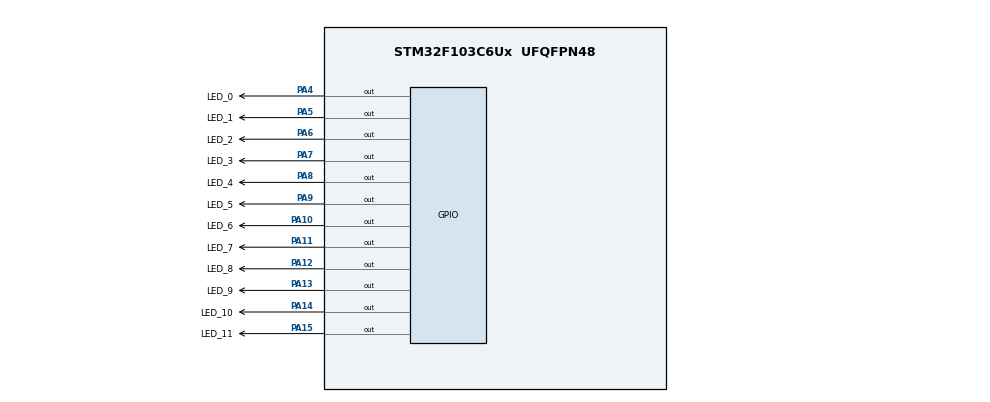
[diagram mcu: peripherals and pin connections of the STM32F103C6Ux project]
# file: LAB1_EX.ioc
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Mcu.Family=STM32F1
Mcu.Name=STM32F103C6Ux
Mcu.Package=UFQFPN48
NVIC.PriorityGroup=NVIC_PRIORITYGROUP_4
PA10.GPIO_Label=LED_6
PA10.Signal=GPIO_Output
PA11.GPIO_Label=LED_7
PA11.Signal=GPIO_Output
PA12.GPIO_Label=LED_8
PA12.Signal=GPIO_Output
PA13.GPIO_Label=LED_9
PA13.Signal=GPIO_Output
PA14.GPIO_Label=LED_10
PA14.Signal=GPIO_Output
PA15.GPIO_Label=LED_11
PA15.Signal=GPIO_Output
PA4.GPIO_Label=LED_0
PA4.Signal=GPIO_Output
PA5.GPIO_Label=LED_1
PA5.Signal=GPIO_Output
PA6.GPIO_Label=LED_2
PA6.Signal=GPIO_Output
PA7.GPIO_Label=LED_3
PA7.Signal=GPIO_Output
PA8.GPIO_Label=LED_4
PA8.Signal=GPIO_Output
PA9.GPIO_Label=LED_5
PA9.Signal=GPIO_Output
ProjectManager.HeapSize=0x200
ProjectManager.StackSize=0x400
ProjectManager.TargetToolchain=STM32CubeIDE
RCC.APB1Freq_Value=8000000
RCC.APB2Freq_Value=8000000
VP_SYS_VS_ND.Mode=No_Debug
board=custom

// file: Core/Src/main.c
/* USER CODE BEGIN Header */
/**
  ******************************************************************************
  * @file           : main.c
  * @brief          : Main program body
  ******************************************************************************
  * @attention
  *
  * <h2><center>&copy; Copyright (c) 2023 STMicroelectronics.
  * All rights reserved.</center></h2>
  *
  * This software component is licensed by ST under BSD 3-Clause license,
  * the "License"; You may not use this file except in compliance with the
  * License. You may obtain a copy of the License at:
  *                        opensource.org/licenses/BSD-3-Clause
  *
  ******************************************************************************
  */
/* USER CODE END Header */
#include "main.h"

void SystemClock_Config(void);
static void MX_GPIO_Init(void);

/* USER CODE BEGIN 0 */
enum LedState
{
	R1_G2,
	R1_Y2,
	G1_R2,
	Y1_R2,
};
enum LED
{
	R1,
	R2,
	G1,
	G2,
	Y1,
	Y2,
};
void turnOnLed(enum LED led)
{
	switch (led)
	{
		case R1:
			HAL_GPIO_WritePin(LED_RED_GPIO_Port, LED_RED_Pin, 0);
			HAL_GPIO_WritePin(LED_GREEN_GPIO_Port, LED_GREEN_Pin, 1);
			HAL_GPIO_WritePin(LED_YELLOW_GPIO_Port, LED_YELLOW_Pin, 1);
			break;
		case R2:
			HAL_GPIO_WritePin(LED_RED2_GPIO_Port, LED_RED2_Pin, 0);
			HAL_GPIO_WritePin(LED_GREEN2_GPIO_Port, LED_GREEN2_Pin, 1);
			HAL_GPIO_WritePin(LED_YELLOW2_GPIO_Port, LED_YELLOW2_Pin, 1);
			break;
		case G1:
			HAL_GPIO_WritePin(LED_RED_GPIO_Port, LED_RED_Pin, 1);
			HAL_GPIO_WritePin(LED_GREEN_GPIO_Port, LED_GREEN_Pin, 0);
			HAL_GPIO_WritePin(LED_YELLOW_GPIO_Port, LED_YELLOW_Pin, 1);
			break;
		case G2:
			HAL_GPIO_WritePin(LED_RED2_GPIO_Port, LED_RED2_Pin, 1);
			HAL_GPIO_WritePin(LED_GREEN2_GPIO_Port, LED_GREEN2_Pin, 0);
			HAL_GPIO_WritePin(LED_YELLOW2_GPIO_Port, LED_YELLOW2_Pin, 1);
			break;
		case Y1:
			HAL_GPIO_WritePin(LED_RED_GPIO_Port, LED_RED_Pin, 1);
			HAL_GPIO_WritePin(LED_GREEN_GPIO_Port, LED_GREEN_Pin, 1);
			HAL_GPIO_WritePin(LED_YELLOW_GPIO_Port, LED_YELLOW_Pin, 0);
			break;
		case Y2:
			HAL_GPIO_WritePin(LED_RED2_GPIO_Port, LED_RED2_Pin, 1);
			HAL_GPIO_WritePin(LED_GREEN2_GPIO_Port, LED_GREEN2_Pin, 1);
			HAL_GPIO_WritePin(LED_YELLOW2_GPIO_Port, LED_YELLOW2_Pin, 0);
			break;
		default:
			break;
	}
}

void display7SEG(int num)
{
	  if(num == 0)
	  {
		  HAL_GPIO_WritePin(SEGMENT_A_GPIO_Port, SEGMENT_A_Pin, 0);
		  HAL_GPIO_WritePin(SEGMENT_B_GPIO_Port, SEGMENT_B_Pin, 0);
		  HAL_GPIO_WritePin(SEGMENT_C_GPIO_Port, SEGMENT_C_Pin, 0);
		  HAL_GPIO_WritePin(SEGMENT_D_GPIO_Port, SEGMENT_D_Pin, 0);
		  HAL_GPIO_WritePin(SEGMENT_E_GPIO_Port, SEGMENT_E_Pin, 0);
		  HAL_GPIO_WritePin(SEGMENT_F_GPIO_Port, SEGMENT_F_Pin, 0);
		  HAL_GPIO_WritePin(SEGMENT_G_GPIO_Port, SEGMENT_G_Pin, 1);

	  }
	  if(num == 1)
	  {
		  HAL_GPIO_WritePin(SEGMENT_A_GPIO_Port, SEGMENT_A_Pin, 1);
		  HAL_GPIO_WritePin(SEGMENT_B_GPIO_Port, SEGMENT_B_Pin, 0);
		  HAL_GPIO_WritePin(SEGMENT_C_GPIO_Port, SEGMENT_C_Pin, 0);
		  HAL_GPIO_WritePin(SEGMENT_D_GPIO_Port, SEGMENT_D_Pin, 1);
		  HAL_GPIO_WritePin(SEGMENT_E_GPIO_Port, SEGMENT_E_Pin, 1);
		  HAL_GPIO_WritePin(SEGMENT_F_GPIO_Port, SEGMENT_F_Pin, 1);
		  HAL_GPIO_WritePin(SEGMENT_G_GPIO_Port, SEGMENT_G_Pin, 1);
	  }
	  if(num == 2)
	  {
		  HAL_GPIO_WritePin(SEGMENT_A_GPIO_Port, SEGMENT_A_Pin, 0);
		  HAL_GPIO_WritePin(SEGMENT_B_GPIO_Port, SEGMENT_B_Pin, 0);
		  HAL_GPIO_WritePin(SEGMENT_C_GPIO_Port, SEGMENT_C_Pin, 1);
		  HAL_GPIO_WritePin(SEGMENT_D_GPIO_Port, SEGMENT_D_Pin, 0);
		  HAL_GPIO_WritePin(SEGMENT_E_GPIO_Port, SEGMENT_E_Pin, 0);
		  HAL_GPIO_WritePin(SEGMENT_F_GPIO_Port, SEGMENT_F_Pin, 1);
		  HAL_GPIO_WritePin(SEGMENT_G_GPIO_Port, SEGMENT_G_Pin, 0);
	  }
	  if(num == 3)
	  {
		  HAL_GPIO_WritePin(SEGMENT_A_GPIO_Port, SEGMENT_A_Pin, 0);
		  HAL_GPIO_WritePin(SEGMENT_B_GPIO_Port, SEGMENT_B_Pin, 0);
		  HAL_GPIO_WritePin(SEGMENT_C_GPIO_Port, SEGMENT_C_Pin, 0);
		  HAL_GPIO_WritePin(SEGMENT_D_GPIO_Port, SEGMENT_D_Pin, 0);
		  HAL_GPIO_WritePin(SEGMENT_E_GPIO_Port, SEGMENT_E_Pin, 1);
		  HAL_GPIO_WritePin(SEGMENT_F_GPIO_Port, SEGMENT_F_Pin, 1);
		  HAL_GPIO_WritePin(SEGMENT_G_GPIO_Port, SEGMENT_G_Pin, 0);
	  }
	  if(num == 4)
	  {
		  HAL_GPIO_WritePin(SEGMENT_A_GPIO_Port, SEGMENT_A_Pin, 1);
		  HAL_GPIO_WritePin(SEGMENT_B_GPIO_Port, SEGMENT_B_Pin, 0);
		  HAL_GPIO_WritePin(SEGMENT_C_GPIO_Port, SEGMENT_C_Pin, 0);
		  HAL_GPIO_WritePin(SEGMENT_D_GPIO_Port, SEGMENT_D_Pin, 1);
		  HAL_GPIO_WritePin(SEGMENT_E_GPIO_Port, SEGMENT_E_Pin, 1);
		  HAL_GPIO_WritePin(SEGMENT_F_GPIO_Port, SEGMENT_F_Pin, 0);
		  HAL_GPIO_WritePin(SEGMENT_G_GPIO_Port, SEGMENT_G_Pin, 0);
	  }
	  if(num == 5)
	  {
		  HAL_GPIO_WritePin(SEGMENT_A_GPIO_Port, SEGMENT_A_Pin, 0);
		  HAL_GPIO_WritePin(SEGMENT_B_GPIO_Port, SEGMENT_B_Pin, 1);
		  HAL_GPIO_WritePin(SEGMENT_C_GPIO_Port, SEGMENT_C_Pin, 0);
		  HAL_GPIO_WritePin(SEGMENT_D_GPIO_Port, SEGMENT_D_Pin, 0);
		  HAL_GPIO_WritePin(SEGMENT_E_GPIO_Port, SEGMENT_E_Pin, 1);
		  HAL_GPIO_WritePin(SEGMENT_F_GPIO_Port, SEGMENT_F_Pin, 0);
		  HAL_GPIO_WritePin(SEGMENT_G_GPIO_Port, SEGMENT_G_Pin, 0);
	  }
	  if(num == 6)
	  {
		  HAL_GPIO_WritePin(SEGMENT_A_GPIO_Port, SEGMENT_A_Pin, 0);
		  HAL_GPIO_WritePin(SEGMENT_B_GPIO_Port, SEGMENT_B_Pin, 1);
		  HAL_GPIO_WritePin(SEGMENT_C_GPIO_Port, SEGMENT_C_Pin, 0);
		  HAL_GPIO_WritePin(SEGMENT_D_GPIO_Port, SEGMENT_D_Pin, 0);
		  HAL_GPIO_WritePin(SEGMENT_E_GPIO_Port, SEGMENT_E_Pin, 0);
		  HAL_GPIO_WritePin(SEGMENT_F_GPIO_Port, SEGMENT_F_Pin, 0);
		  HAL_GPIO_WritePin(SEGMENT_G_GPIO_Port, SEGMENT_G_Pin, 0);
	  }
	  if(num == 7)
	  {
		  HAL_GPIO_WritePin(SEGMENT_A_GPIO_Port, SEGMENT_A_Pin, 0);
		  HAL_GPIO_WritePin(SEGMENT_B_GPIO_Port, SEGMENT_B_Pin, 0);
		  HAL_GPIO_WritePin(SEGMENT_C_GPIO_Port, SEGMENT_C_Pin, 0);
		  HAL_GPIO_WritePin(SEGMENT_D_GPIO_Port, SEGMENT_D_Pin, 1);
		  HAL_GPIO_WritePin(SEGMENT_E_GPIO_Port, SEGMENT_E_Pin, 1);
		  HAL_GPIO_WritePin(SEGMENT_F_GPIO_Port, SEGMENT_F_Pin, 1);
		  HAL_GPIO_WritePin(SEGMENT_G_GPIO_Port, SEGMENT_G_Pin, 1);
	  }
	  if(num == 8)
	  {
		  HAL_GPIO_WritePin(SEGMENT_A_GPIO_Port, SEGMENT_A_Pin, 0);
		  HAL_GPIO_WritePin(SEGMENT_B_GPIO_Port, SEGMENT_B_Pin, 0);
		  HAL_GPIO_WritePin(SEGMENT_C_GPIO_Port, SEGMENT_C_Pin, 0);
		  HAL_GPIO_WritePin(SEGMENT_D_GPIO_Port, SEGMENT_D_Pin, 0);
		  HAL_GPIO_WritePin(SEGMENT_E_GPIO_Port, SEGMENT_E_Pin, 0);
		  HAL_GPIO_WritePin(SEGMENT_F_GPIO_Port, SEGMENT_F_Pin, 0);
		  HAL_GPIO_WritePin(SEGMENT_G_GPIO_Port, SEGMENT_G_Pin, 0);
	  }
	  if(num == 9)
	  {
		  HAL_GPIO_WritePin(SEGMENT_A_GPIO_Port, SEGMENT_A_Pin, 0);
		  HAL_GPIO_WritePin(SEGMENT_B_GPIO_Port, SEGMENT_B_Pin, 0);
		  HAL_GPIO_WritePin(SEGMENT_C_GPIO_Port, SEGMENT_C_Pin, 0);
		  HAL_GPIO_WritePin(SEGMENT_D_GPIO_Port, SEGMENT_D_Pin, 0);
		  HAL_GPIO_WritePin(SEGMENT_E_GPIO_Port, SEGMENT_E_Pin, 1);
		  HAL_GPIO_WritePin(SEGMENT_F_GPIO_Port, SEGMENT_F_Pin, 0);
		  HAL_GPIO_WritePin(SEGMENT_G_GPIO_Port, SEGMENT_G_Pin, 0);
	  }
}
// 7SEG 2
void display7SEG2(int num)
  {
	  if(num == 0)
	  {
		  HAL_GPIO_WritePin(SEGMENT_A2_GPIO_Port, SEGMENT_A2_Pin, 0);
		  HAL_GPIO_WritePin(SEGMENT_B2_GPIO_Port, SEGMENT_B2_Pin, 0);
		  HAL_GPIO_WritePin(SEGMENT_C2_GPIO_Port, SEGMENT_C2_Pin, 0);
		  HAL_GPIO_WritePin(SEGMENT_D2_GPIO_Port, SEGMENT_D2_Pin, 0);
		  HAL_GPIO_WritePin(SEGMENT_E2_GPIO_Port, SEGMENT_E2_Pin, 0);
		  HAL_GPIO_WritePin(SEGMENT_F2_GPIO_Port, SEGMENT_F2_Pin, 0);
		  HAL_GPIO_WritePin(SEGMENT_G2_GPIO_Port, SEGMENT_G2_Pin, 1);

	  }
	  if(num == 1)
	  {
		  HAL_GPIO_WritePin(SEGMENT_A2_GPIO_Port, SEGMENT_A2_Pin, 1);
		  HAL_GPIO_WritePin(SEGMENT_B2_GPIO_Port, SEGMENT_B2_Pin, 0);
		  HAL_GPIO_WritePin(SEGMENT_C2_GPIO_Port, SEGMENT_C2_Pin, 0);
		  HAL_GPIO_WritePin(SEGMENT_D2_GPIO_Port, SEGMENT_D2_Pin, 1);
		  HAL_GPIO_WritePin(SEGMENT_E2_GPIO_Port, SEGMENT_E2_Pin, 1);
		  HAL_GPIO_WritePin(SEGMENT_F2_GPIO_Port, SEGMENT_F2_Pin, 1);
		  HAL_GPIO_WritePin(SEGMENT_G2_GPIO_Port, SEGMENT_G2_Pin, 1);
	  }
	  if(num == 2)
	  {
		  HAL_GPIO_WritePin(SEGMENT_A2_GPIO_Port, SEGMENT_A2_Pin, 0);
		  HAL_GPIO_WritePin(SEGMENT_B2_GPIO_Port, SEGMENT_B2_Pin, 0);
		  HAL_GPIO_WritePin(SEGMENT_C2_GPIO_Port, SEGMENT_C2_Pin, 1);
		  HAL_GPIO_WritePin(SEGMENT_D2_GPIO_Port, SEGMENT_D2_Pin, 0);
		  HAL_GPIO_WritePin(SEGMENT_E2_GPIO_Port, SEGMENT_E2_Pin, 0);
		  HAL_GPIO_WritePin(SEGMENT_F2_GPIO_Port, SEGMENT_F2_Pin, 1);
		  HAL_GPIO_WritePin(SEGMENT_G2_GPIO_Port, SEGMENT_G2_Pin, 0);
	  }
	  if(num == 3)
	  {
		  HAL_GPIO_WritePin(SEGMENT_A2_GPIO_Port, SEGMENT_A2_Pin, 0);
		  HAL_GPIO_WritePin(SEGMENT_B2_GPIO_Port, SEGMENT_B2_Pin, 0);
		  HAL_GPIO_WritePin(SEGMENT_C2_GPIO_Port, SEGMENT_C2_Pin, 0);
		  HAL_GPIO_WritePin(SEGMENT_D2_GPIO_Port, SEGMENT_D2_Pin, 0);
		  HAL_GPIO_WritePin(SEGMENT_E2_GPIO_Port, SEGMENT_E2_Pin, 1);
		  HAL_GPIO_WritePin(SEGMENT_F2_GPIO_Port, SEGMENT_F2_Pin, 1);
		  HAL_GPIO_WritePin(SEGMENT_G2_GPIO_Port, SEGMENT_G2_Pin, 0);
	  }
	  if(num == 4)
	  {
		  HAL_GPIO_WritePin(SEGMENT_A2_GPIO_Port, SEGMENT_A2_Pin, 1);
		  HAL_GPIO_WritePin(SEGMENT_B2_GPIO_Port, SEGMENT_B2_Pin, 0);
		  HAL_GPIO_WritePin(SEGMENT_C2_GPIO_Port, SEGMENT_C2_Pin, 0);
		  HAL_GPIO_WritePin(SEGMENT_D2_GPIO_Port, SEGMENT_D2_Pin, 1);
		  HAL_GPIO_WritePin(SEGMENT_E2_GPIO_Port, SEGMENT_E2_Pin, 1);
		  HAL_GPIO_WritePin(SEGMENT_F2_GPIO_Port, SEGMENT_F2_Pin, 0);
		  HAL_GPIO_WritePin(SEGMENT_G2_GPIO_Port, SEGMENT_G2_Pin, 0);
	  }
	  if(num == 5)
	  {
		  HAL_GPIO_WritePin(SEGMENT_A2_GPIO_Port, SEGMENT_A2_Pin, 0);
		  HAL_GPIO_WritePin(SEGMENT_B2_GPIO_Port, SEGMENT_B2_Pin, 1);
		  HAL_GPIO_WritePin(SEGMENT_C2_GPIO_Port, SEGMENT_C2_Pin, 0);
		  HAL_GPIO_WritePin(SEGMENT_D2_GPIO_Port, SEGMENT_D2_Pin, 0);
		  HAL_GPIO_WritePin(SEGMENT_E2_GPIO_Port, SEGMENT_E2_Pin, 1);
		  HAL_GPIO_WritePin(SEGMENT_F2_GPIO_Port, SEGMENT_F2_Pin, 0);
		  HAL_GPIO_WritePin(SEGMENT_G2_GPIO_Port, SEGMENT_G2_Pin, 0);
	  }
	  if(num == 6)
	  {
		  HAL_GPIO_WritePin(SEGMENT_A2_GPIO_Port, SEGMENT_A2_Pin, 0);
		  HAL_GPIO_WritePin(SEGMENT_B2_GPIO_Port, SEGMENT_B2_Pin, 1);
		  HAL_GPIO_WritePin(SEGMENT_C2_GPIO_Port, SEGMENT_C2_Pin, 0);
		  HAL_GPIO_WritePin(SEGMENT_D2_GPIO_Port, SEGMENT_D2_Pin, 0);
		  HAL_GPIO_WritePin(SEGMENT_E2_GPIO_Port, SEGMENT_E2_Pin, 0);
		  HAL_GPIO_WritePin(SEGMENT_F2_GPIO_Port, SEGMENT_F2_Pin, 0);
		  HAL_GPIO_WritePin(SEGMENT_G2_GPIO_Port, SEGMENT_G2_Pin, 0);
	  }
	  if(num == 7)
	  {
		  HAL_GPIO_WritePin(SEGMENT_A2_GPIO_Port, SEGMENT_A2_Pin, 0);
		  HAL_GPIO_WritePin(SEGMENT_B2_GPIO_Port, SEGMENT_B2_Pin, 0);
		  HAL_GPIO_WritePin(SEGMENT_C2_GPIO_Port, SEGMENT_C2_Pin, 0);
		  HAL_GPIO_WritePin(SEGMENT_D2_GPIO_Port, SEGMENT_D2_Pin, 1);
		  HAL_GPIO_WritePin(SEGMENT_E2_GPIO_Port, SEGMENT_E2_Pin, 1);
		  HAL_GPIO_WritePin(SEGMENT_F2_GPIO_Port, SEGMENT_F2_Pin, 1);
		  HAL_GPIO_WritePin(SEGMENT_G2_GPIO_Port, SEGMENT_G2_Pin, 1);
	  }
	  if(num == 8)
	  {
		  HAL_GPIO_WritePin(SEGMENT_A2_GPIO_Port, SEGMENT_A2_Pin, 0);
		  HAL_GPIO_WritePin(SEGMENT_B2_GPIO_Port, SEGMENT_B2_Pin, 0);
		  HAL_GPIO_WritePin(SEGMENT_C2_GPIO_Port, SEGMENT_C2_Pin, 0);
		  HAL_GPIO_WritePin(SEGMENT_D2_GPIO_Port, SEGMENT_D2_Pin, 0);
		  HAL_GPIO_WritePin(SEGMENT_E2_GPIO_Port, SEGMENT_E2_Pin, 0);
		  HAL_GPIO_WritePin(SEGMENT_F2_GPIO_Port, SEGMENT_F2_Pin, 0);
		  HAL_GPIO_WritePin(SEGMENT_G2_GPIO_Port, SEGMENT_G2_Pin, 0);
	  }
	  if(num == 9)
	  {
		  HAL_GPIO_WritePin(SEGMENT_A2_GPIO_Port, SEGMENT_A2_Pin, 0);
		  HAL_GPIO_WritePin(SEGMENT_B2_GPIO_Port, SEGMENT_B2_Pin, 0);
		  HAL_GPIO_WritePin(SEGMENT_C2_GPIO_Port, SEGMENT_C2_Pin, 0);
		  HAL_GPIO_WritePin(SEGMENT_D2_GPIO_Port, SEGMENT_D2_Pin, 0);
		  HAL_GPIO_WritePin(SEGMENT_E2_GPIO_Port, SEGMENT_E2_Pin, 1);
		  HAL_GPIO_WritePin(SEGMENT_F2_GPIO_Port, SEGMENT_F2_Pin, 0);
		  HAL_GPIO_WritePin(SEGMENT_G2_GPIO_Port, SEGMENT_G2_Pin, 0);
	  }
  }
/* USER CODE END 0 */

int main(void)
{
  /* USER CODE BEGIN 1 */
	int counter = 3;
	int light1 = 4;
	int light2 = 2;

	enum LedState currentState = R1_G2;
  /* USER CODE END 1 */

  /* MCU Configuration--------------------------------------------------------*/

  /* Reset of all peripherals, Initializes the Flash interface and the Systick. */
  HAL_Init();

  /* Configure the system clock */
  SystemClock_Config();

  /* Initialize all configured peripherals */
  MX_GPIO_Init();

  /* Infinite loop */
  /* USER CODE BEGIN WHILE */

while (1)
{
    	display7SEG(light1);
    	display7SEG2(light2);
    	light1--;
    	light2--;
	 	counter--;
    	switch (currentState)
    		 {
    		 case R1_G2:
    			 turnOnLed(R1);
    			 turnOnLed(G2);
    			 if (counter <= 0)
    			 {
    				 counter = 2;
    				 currentState = R1_Y2;
    				 light2 = 1;
    			 }
    			 break;
    		 case R1_Y2:
    			 turnOnLed(R1);
    			 turnOnLed(Y2);
    			 if (counter <= 0)
    			 {
    				 counter = 3;
    				 currentState = G1_R2;
    				 light1 = 2;
    				 light2 = 4;
    			 }
    			 break;
    		 case G1_R2:
    			 turnOnLed(G1);
    			 turnOnLed(R2);
    			 if (counter <= 0)
    			 {
    				 counter = 2;
    				 currentState = Y1_R2;
    				 light1 = 1;

    			 }
    			 break;
    		 case Y1_R2:
    		 	 turnOnLed(Y1);
    		 	 turnOnLed(R2);
    		 	 if (counter <= 0)
    		 	 {
    		 		 counter = 3;
    		 		 currentState = R1_G2;
    		 		 light1 = 4;
    		 		 light2 = 2;

    		 	 }
    		 	 break;
    		 }
  	 HAL_Delay(1000);

    /* USER CODE END WHILE */

    }
}

void SystemClock_Config(void)
{
  RCC_OscInitTypeDef RCC_OscInitStruct = {0};
  RCC_ClkInitTypeDef RCC_ClkInitStruct = {0};

  /** Initializes the RCC Oscillators according to the specified parameters
  * in the RCC_OscInitTypeDef structure.
  */
  RCC_OscInitStruct.OscillatorType = RCC_OSCILLATORTYPE_HSI;
  RCC_OscInitStruct.HSIState = RCC_HSI_ON;
  RCC_OscInitStruct.HSICalibrationValue = RCC_HSICALIBRATION_DEFAULT;
  RCC_OscInitStruct.PLL.PLLState = RCC_PLL_NONE;
  if (HAL_RCC_OscConfig(&RCC_OscInitStruct) != HAL_OK)
  {
    Error_Handler();
  }
  /** Initializes the CPU, AHB and APB buses clocks
  */
  RCC_ClkInitStruct.ClockType = RCC_CLOCKTYPE_HCLK|RCC_CLOCKTYPE_SYSCLK
                              |RCC_CLOCKTYPE_PCLK1|RCC_CLOCKTYPE_PCLK2;
  RCC_ClkInitStruct.SYSCLKSource = RCC_SYSCLKSOURCE_HSI;
  RCC_ClkInitStruct.AHBCLKDivider = RCC_SYSCLK_DIV1;
  RCC_ClkInitStruct.APB1CLKDivider = RCC_HCLK_DIV1;
  RCC_ClkInitStruct.APB2CLKDivider = RCC_HCLK_DIV1;

  if (HAL_RCC_ClockConfig(&RCC_ClkInitStruct, FLASH_LATENCY_0) != HAL_OK)
  {
    Error_Handler();
  }
}

static void MX_GPIO_Init(void)
{
  GPIO_InitTypeDef GPIO_InitStruct = {0};

  /* GPIO Ports Clock Enable */
  __HAL_RCC_GPIOA_CLK_ENABLE();
  __HAL_RCC_GPIOB_CLK_ENABLE();

  /*Configure GPIO pin Output Level */
  HAL_GPIO_WritePin(GPIOA, LED_RED_Pin|LED_YELLOW_Pin|LED_GREEN_Pin|LED_RED2_Pin
                          |LED_YELLOW2_Pin|LED_GREEN2_Pin, GPIO_PIN_RESET);

  /*Configure GPIO pin Output Level */
  HAL_GPIO_WritePin(GPIOB, SEGMENT_A_Pin|SEGMENT_B_Pin|SEGMENT_C_Pin|SEGMENT_D2_Pin
                          |SEGMENT_E2_Pin|SEGMENT_F2_Pin|SEGMENT_G2_Pin|SEGMENT_D_Pin
                          |SEGMENT_E_Pin|SEGMENT_F_Pin|SEGMENT_G_Pin|SEGMENT_A2_Pin
                          |SEGMENT_B2_Pin|SEGMENT_C2_Pin, GPIO_PIN_RESET);

  /*Configure GPIO pins : LED_RED_Pin LED_YELLOW_Pin LED_GREEN_Pin LED_RED2_Pin
                           LED_YELLOW2_Pin LED_GREEN2_Pin */
  GPIO_InitStruct.Pin = LED_RED_Pin|LED_YELLOW_Pin|LED_GREEN_Pin|LED_RED2_Pin
                          |LED_YELLOW2_Pin|LED_GREEN2_Pin;
  GPIO_InitStruct.Mode = GPIO_MODE_OUTPUT_PP;
  GPIO_InitStruct.Pull = GPIO_NOPULL;
  GPIO_InitStruct.Speed = GPIO_SPEED_FREQ_LOW;
  HAL_GPIO_Init(GPIOA, &GPIO_InitStruct);

  /*Configure GPIO pins : SEGMENT_A_Pin SEGMENT_B_Pin SEGMENT_C_Pin SEGMENT_D2_Pin
                           SEGMENT_E2_Pin SEGMENT_F2_Pin SEGMENT_G2_Pin SEGMENT_D_Pin
                           SEGMENT_E_Pin SEGMENT_F_Pin SEGMENT_G_Pin SEGMENT_A2_Pin
                           SEGMENT_B2_Pin SEGMENT_C2_Pin */
  GPIO_InitStruct.Pin = SEGMENT_A_Pin|SEGMENT_B_Pin|SEGMENT_C_Pin|SEGMENT_D2_Pin
                          |SEGMENT_E2_Pin|SEGMENT_F2_Pin|SEGMENT_G2_Pin|SEGMENT_D_Pin
                          |SEGMENT_E_Pin|SEGMENT_F_Pin|SEGMENT_G_Pin|SEGMENT_A2_Pin
                          |SEGMENT_B2_Pin|SEGMENT_C2_Pin;
  GPIO_InitStruct.Mode = GPIO_MODE_OUTPUT_PP;
  GPIO_InitStruct.Pull = GPIO_NOPULL;
  GPIO_InitStruct.Speed = GPIO_SPEED_FREQ_LOW;
  HAL_GPIO_Init(GPIOB, &GPIO_InitStruct);

}

void Error_Handler(void)
{
  __disable_irq();
  while (1)
  {
  }
}

/************************ (C) COPYRIGHT STMicroelectronics *****END OF FILE****/
